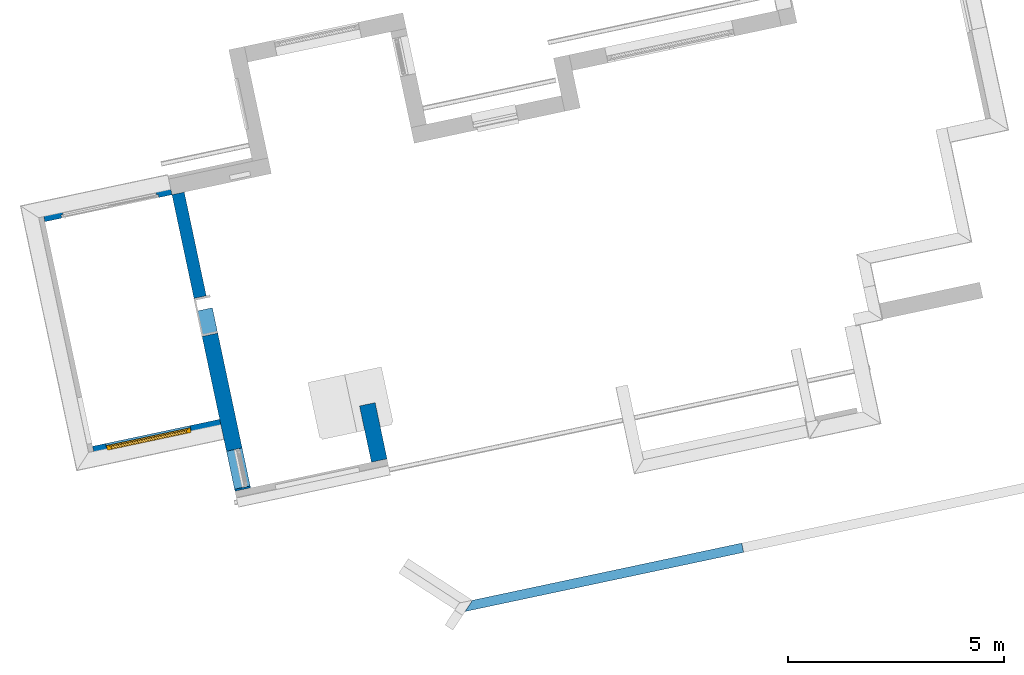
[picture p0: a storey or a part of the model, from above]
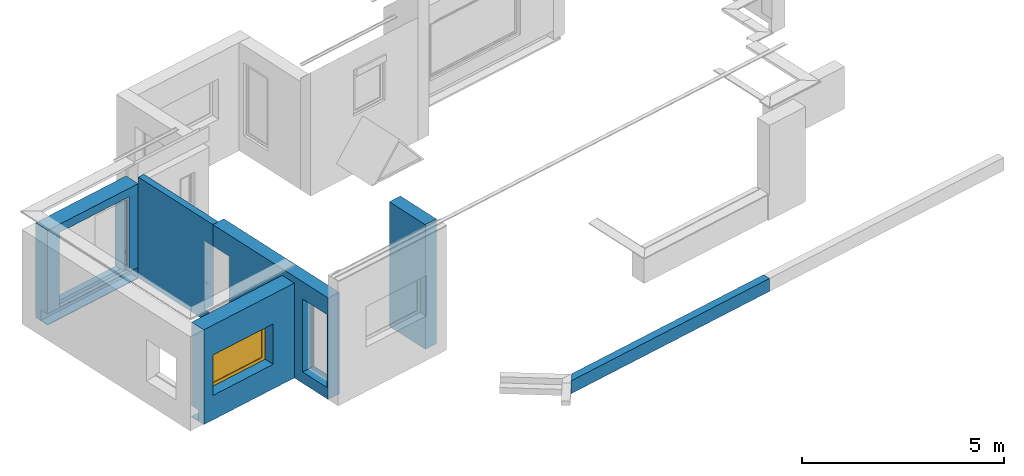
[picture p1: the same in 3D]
Properties of the parts of a building model (IFC2X3)

# File
Description: ViewDefinition [CoordinationView_V2.0], RevitIdentifiers [VersionGUID: 4ad54dfb-f86c-4c14-92f9-87bb07114b9b, NumberOfSaves: 84], CoordinateReference [CoordinateBase: Coordonnées partagées actuelles]
File name: MAI-1014-PORDIC
Time: 2024-04-09T16:30:19
Written by: The EXPRESS Data Manager Version 5.02.0100.07 : 28 Aug 2013
Made in: 22.0.2.392 - Exporter 22.6.0.0 - Interface alternative d'export 22.6.0.0
Comment: STEP Physical File produced by: The EXPRESS Data Manager Version 5.02.0100.07 : 28 Aug 2013 * Module: EDMstepFileFactory/EDMstandAlone * Creation date: Tue Apr 09 16:30:19 2024 * Host: LAPTOP-C1R9780E * Database: C:\Users\olivier\AppData\Local\Temp\71b0d7dc-91db-41fd-8e0b-7346815324da\59c9abdc-0e41-45ae-9ef3-d0277ee2119c\ifc * Database version: 5507 * Database creation date: Tue Apr 09 16:30:01 2024 * Schema: IFC2X3 * Model: DataRepository.ifc * Model creation date: Tue Apr 09 16:30:05 2024 * Header model: DataRepository.ifc_HeaderModel * Header model creation date: Tue Apr 09 16:30:05 2024 * EDMuser: sdai-user * EDMgroup: sdai-group * License ID and type: 5605 : Permanent license. Expiry date: * EDMstepFileFactory options: 020000

# IfcProject, MAI-1014-PORDIC
LongName: Extension d'une maison individuelle à Pordic; Phase: PC

# IfcSite, Surface:739914
RefLatitude: 48, 35, 2, 357482; RefLongitude: -2, -47, -1, -321678; RefElevation: 0 cm

# IfcBuilding
Pset_BuildingCommon - NumberOfStoreys: 7

# IfcBuildingStorey: Niveau:Ligne du (SD) Niveau_Projet 200, ***R+1 (SD)***
LongName: ***R+1 (SD)***; Elevation: 269 cm

# IfcBuildingStorey: Niveau:Ligne du Niveau (SD)_Partagée NGF 200 (2)
Name | LongName | Elevation (cm)
Rez de chaussée (SD) | Rez de chaussée (SD) | -17
***R+2 (SD)*** | ***R+2 (SD)*** | 522

# IfcBuildingStorey: Niveau:Ligne du Niveau_Partagée NGF 200, _R+2
LongName: _R+2; Elevation: 544 cm

# IfcBuildingStorey: Niveau:Ligne du Niveau_Projet 200 (3)
Name | LongName | Elevation (cm)
_Rez de chaussée Séjour | _Rez de chaussée Séjour | 2.07728e-10
Rez de chaussée | Rez de chaussée | 17
_R+1 | _R+1 | 289

# IfcSpace: Bain Etage 9:4713626, 9
In: _R+1
LongName: Bain Etage; InteriorOrExteriorSpace: INTERNAL
Pset_SpaceCommon - Reference: Bain Etage 9

# IfcSpace: Bain2 Etage 14:4713631, 14
In: _R+1
LongName: Bain2 Etage; InteriorOrExteriorSpace: INTERNAL
Pset_SpaceCommon - Reference: Bain2 Etage 14

# IfcSpace: Buanderie 10:4713627, 10
In: _R+1
LongName: Buanderie; InteriorOrExteriorSpace: INTERNAL
Pset_SpaceCommon - Reference: Buanderie 10

# IfcSpace: Buanderie ccc:4481670, ccc
In: _Rez de chaussée Séjour
LongName: Buanderie; InteriorOrExteriorSpace: INTERNAL
Pset_SpaceCommon - Reference: Buanderie ccc

# IfcSpace: Chambre 1 lll:4844613, lll
In: _Rez de chaussée Séjour
LongName: Chambre 1; InteriorOrExteriorSpace: INTERNAL
Pset_SpaceCommon - Reference: Chambre 1 lll

# IfcSpace: Chambre 11:4713628, 11
In: _R+1
LongName: Chambre; InteriorOrExteriorSpace: INTERNAL
Pset_SpaceCommon - Reference: Chambre 11

# IfcSpace: Chambre 15:4713632, 15
In: _R+1
LongName: Chambre; InteriorOrExteriorSpace: INTERNAL
Pset_SpaceCommon - Reference: Chambre 15

# IfcSpace: Chambre 2 zz:4481613, zz
In: _Rez de chaussée Séjour
LongName: Chambre 2; InteriorOrExteriorSpace: INTERNAL
Pset_SpaceCommon - Reference: Chambre 2 zz

# IfcSpace: Chambre 3 aaa:4481619, aaa
In: _Rez de chaussée Séjour
LongName: Chambre 3; InteriorOrExteriorSpace: INTERNAL
Pset_SpaceCommon - Reference: Chambre 3 aaa

# IfcSpace: Cuisine jjj:4483339, jjj
In: _Rez de chaussée Séjour
LongName: Cuisine; InteriorOrExteriorSpace: INTERNAL
Pset_SpaceCommon - Reference: Cuisine jjj

# IfcSpace: Dgt. 13:4713630, 13
In: _R+1
LongName: Dgt.; InteriorOrExteriorSpace: INTERNAL
Pset_SpaceCommon - Reference: Dgt. 13

# IfcSpace: Dgt. 16:4717892, 16
In: _R+1
LongName: Dgt.; InteriorOrExteriorSpace: INTERNAL
Pset_SpaceCommon - Reference: Dgt. 16

# IfcSpace: Dgt. ddd:4481676, ddd
In: _Rez de chaussée Séjour
LongName: Dgt.; InteriorOrExteriorSpace: INTERNAL
Pset_SpaceCommon - Reference: Dgt. ddd

# IfcSpace: Espace vert 12:2006179, 12
In: _Rez de chaussée Séjour
LongName: Espace vert; InteriorOrExteriorSpace: INTERNAL; Group: PARCELLES
Pset_SpaceCommon - Reference: Espace vert 12

# IfcSpace: Hall fff:4481931, fff
In: _Rez de chaussée Séjour
LongName: Hall; InteriorOrExteriorSpace: INTERNAL
Pset_SpaceCommon - Reference: Hall fff

# IfcSpace: Lot 1 8:2006171, 8
In: _Rez de chaussée Séjour
LongName: Lot 1; InteriorOrExteriorSpace: INTERNAL; Group: PARCELLES
Pset_SpaceCommon - Reference: Lot 1 8

# IfcSpace: Lot 2 10:2006175, 10
In: _Rez de chaussée Séjour
LongName: Lot 2; InteriorOrExteriorSpace: INTERNAL; Group: PARCELLES
Pset_SpaceCommon - Reference: Lot 2 10

# IfcSpace: Lot 3 11:2006177, 11
In: _Rez de chaussée Séjour
LongName: Lot 3; InteriorOrExteriorSpace: INTERNAL; Group: PARCELLES
Pset_SpaceCommon - Reference: Lot 3 11

# IfcSpace: Mezzanine 12:4713629, 12
In: _R+1
LongName: Mezzanine; InteriorOrExteriorSpace: INTERNAL
Pset_SpaceCommon - Reference: Mezzanine 12

# IfcSpace: SDE eee:4481930, eee
In: _Rez de chaussée Séjour
LongName: SDE; InteriorOrExteriorSpace: INTERNAL
Pset_SpaceCommon - Reference: SDE eee

# IfcSpace: SDE yy:4481608, yy
In: _Rez de chaussée Séjour
LongName: SDE; InteriorOrExteriorSpace: INTERNAL
Pset_SpaceCommon - Reference: SDE yy

# IfcSpace: STnd 159:1942835, 159
In: _Rez de chaussée Séjour
LongName: STnd; InteriorOrExteriorSpace: INTERNAL; Group: SURFACE DE PLANCHER (existant)
Pset_SpaceCommon - Reference: STnd 159

# IfcSpace: STnd 1:4682735, 1
In: _Rez de chaussée Séjour
LongName: STnd; InteriorOrExteriorSpace: INTERNAL; Group: SURFACE DE PLANCHER (projet)
Pset_SpaceCommon - Reference: STnd 1

# IfcSpace: Salle à manger iii:4483313, iii
In: _Rez de chaussée Séjour
LongName: Salle à manger; InteriorOrExteriorSpace: INTERNAL
Pset_SpaceCommon - Reference: Salle à manger iii

# IfcSpace: Surface affectée au stationnement des véhicules 216:1942263, 216
In: _Rez de chaussée Séjour
LongName: Surface affectée au stationnement des véhicules; InteriorOrExteriorSpace: INTERNAL; Group: Construction brute
Pset_SpaceCommon - Reference: Surface affectée au stationnement des véhicules 216

# IfcSpace: Surface affectée à l'habitation 214:1942178, 214
In: _Rez de chaussée Séjour
LongName: Surface affectée à l'habitation; InteriorOrExteriorSpace: INTERNAL; Group: Construction brute
Pset_SpaceCommon - Reference: Surface affectée à l'habitation 214

# IfcSpace: Surface technique (RDC ou étage) 215:1942179, 215
In: _Rez de chaussée Séjour
LongName: Surface technique (RDC ou étage); InteriorOrExteriorSpace: INTERNAL; Group: Construction brute
Pset_SpaceCommon - Reference: Surface technique (RDC ou étage) 215

# IfcSpace: Surface technique (sous-sol ou combles) 218:1942282, 218
In: _Rez de chaussée Séjour
LongName: Surface technique (sous-sol ou combles); InteriorOrExteriorSpace: INTERNAL; Group: Construction brute
Pset_SpaceCommon - Reference: Surface technique (sous-sol ou combles) 218

# IfcSpace: Surfaces non closes en RDC, balcons et toitures terrasses 217:1942277, 217
In: _Rez de chaussée Séjour
LongName: Surfaces non closes en RDC, balcons et toitures terrasses; InteriorOrExteriorSpace: INTERNAL; Group: Construction brute
Pset_SpaceCommon - Reference: Surfaces non closes en RDC, balcons et toitures terrasses 217

# IfcSpace: Séjour / Jardin ggg:4482516, ggg
In: _Rez de chaussée Séjour
LongName: Séjour / Jardin; InteriorOrExteriorSpace: INTERNAL
Pset_SpaceCommon - Reference: Séjour / Jardin ggg

# IfcSpace: Séjour / Mer hhh:4482627, hhh
In: _Rez de chaussée Séjour
LongName: Séjour / Mer; InteriorOrExteriorSpace: INTERNAL
Pset_SpaceCommon - Reference: Séjour / Mer hhh

# IfcSpace: Voirie 9:2006173, 9
In: _Rez de chaussée Séjour
LongName: Voirie; InteriorOrExteriorSpace: INTERNAL; Group: PARCELLES
Pset_SpaceCommon - Reference: Voirie 9

# IfcSpace: Wc mmm:4934494, mmm
In: _Rez de chaussée Séjour
LongName: Wc; InteriorOrExteriorSpace: INTERNAL
Pset_SpaceCommon - Reference: Wc mmm

# IfcBeam: Poutre - Bois de construction de dimensions courantes:100x280, Poutre - Bois de construction de dimensions courantes:100x280:5055540
In: ***R+1 (SD)***
Type - Pset_BeamCommon - LoadBearing: yes; IsExternal: no
Material: Bois - Bois de construction de dimensions courantes
Pset_BeamCommon - Reference: 100x280; Span: 189 cm; Slope: 0 deg
Pset_QuantityTakeOff - Reference: 100x280; sets with these values: 2

# IfcBuildingElementProxy: 5028824
In: Rez de chaussée (SD)
Pset_ProvisionForVoid - Shape: Undefined

# IfcBuildingElementProxy: 5114860
In: Rez de chaussée (SD)
Pset_ProvisionForVoid - Shape: Undefined

# IfcBuildingElementProxy: Bord de toiture:Profil Ardoise, Bord de toiture:Profil Ardoise:5044503
In: ***R+2 (SD)***
Pset_BuildingElementProxyCommon - Reference: Profil Ardoise; sets with these values: 2

# IfcBuildingElementProxy: Lave-Mains 40x24:40x24, Lave-Mains 40x24:40x24:4976055
In: mmm
Type - Material: <Unnamed>
Pset_BuildingElementProxyCommon - Reference: 40x24; sets with these values: 2

# IfcBuildingElementProxy: PLANTE- Conifères divers:Pin en tige remontée_ Grand (3)
In: _Rez de chaussée Séjour
Type - Material: <Unnamed>
Classification: G2050500 Uniformat (Uniformat)
Pset_BuildingElementProxyCommon - Reference: Pin en tige remontée_ Grand; sets with these values: 2
Name (PLANTE- Conifères divers:Pin en tige remontée_ Grand:...)
4941498
4942555
5015873

# IfcBuildingElementProxy: PLANTE- Conifères divers:Pin en tige remontée_ Petit (3)
In: _Rez de chaussée Séjour
Type - Material: <Unnamed>
Classification: G2050500 Uniformat (Uniformat)
Pset_BuildingElementProxyCommon - Reference: Pin en tige remontée_ Petit; sets with these values: 2
Name (PLANTE- Conifères divers:Pin en tige remontée_ Petit:...)
4942507
5015922
5015967

# IfcBuildingElementProxy: RES- REGARD:Regard EP 60*60, RES- REGARD:Regard EP 60*60:5132817
In: Rez de chaussée
Type - Material: <Unnamed>
Pset_BuildingElementProxyCommon - Reference: Regard EP 60*60; sets with these values: 2
Pset_ProvisionForVoid - Width: 60 cm; Height: 60 cm; Depth: 60 cm

# IfcBuildingElementProxy: RES_EP - BARBACANE:5x20 (3)
In: _R+1
Type - Material: <Unnamed>
Pset_BuildingElementProxyCommon - Reference: 5x20; sets with these values: 2
Name (RES_EP - BARBACANE:5x20:...)
5134526
5134740
5135031

# IfcBuildingElementProxy: RES_EP - BOITE A EAU:Descente EP _Alu gris clair (3)
In: _R+1
Type - Material: __ ALU_ton gris (descentes EP)
Pset_BuildingElementProxyCommon - Reference: Descente EP _Alu gris clair; sets with these values: 2
Pset_ProvisionForVoid - Width: 20 cm; Height: 20 cm; Depth: 20 cm
Name (RES_EP - BOITE A EAU:Descente EP _Alu gris clair:...)
5130607
5131939
5138986

# IfcColumn: Poteau alu - Carré:20x20, Poteau alu - Carré:20x20:5078782
In: _Rez de chaussée Séjour
Type - PredefinedType: COLUMN; Material: __ METAL_gris foncé (menuiseries acier)______________________TEST
Type - Pset_ColumnCommon - LoadBearing: yes; IsExternal: no
Pset_ColumnCommon - Reference: 20x20
Pset_QuantityTakeOff - Reference: 20x20; sets with these values: 2

# IfcCovering: Plafond composé:*BA13+ suspentes métalliques ISO 30 (4)
In: ***R+1 (SD)***
Type - PredefinedType: CEILING
Type - Pset_CoveringCommon - TotalThickness: 32 cm
Material: Laine minérale 30 cm, __ BA 13 2 cm
Pset_CoveringCommon - Reference: *BA13+ suspentes métalliques ISO 30; sets with these values: 2
Name (Plafond composé:*BA13+ suspentes métalliques ISO 30:...)
4829692
5046348
5074606
5139370

# IfcCurtainWall: Mur-rideau:*Mur-rideau (5)
Type - Pset_CurtainWallCommon - IsExternal: yes
Pset_CurtainWallCommon - Reference: *Mur-rideau
Pset_QuantityTakeOff - Reference: *Mur-rideau
Name (Mur-rideau:*Mur-rideau:...) | In
4793220 | _Rez de chaussée Séjour
4793331 | _R+1
4838392 | _Rez de chaussée Séjour
4839396 | _Rez de chaussée Séjour
5005422 | _Rez de chaussée Séjour

# IfcDoor: *Coulissante - Encastrée:PC 230 x 204 (galandage), *Coulissante - Encastrée:PC 230 x 204 (galandage):4812745
In: _Rez de chaussée Séjour
Type - OperationType: SLIDING_TO_LEFT; ParameterTakesPrecedence: no; Sizeable: no; Material: <Unnamed>
Type - *Coulissante - Encastrée:PC 230 x 204 (galandage):4812745:1 - PanelOperation: SLIDING
Type - Pset_DoorCommon - IsExternal: no
OverallHeight: 206.5 cm; OverallWidth: 460 cm
Pset_DoorCommon - Reference: PC 230 x 204 (galandage)
Pset_QuantityTakeOff - Reference: PC 230 x 204 (galandage)

# IfcDoor: *Coulissante - Encastrée:PC 80 x 204 (galandage), *Coulissante - Encastrée:PC 80 x 204 (galandage):4673256
In: Rez de chaussée
Type - OperationType: SLIDING_TO_LEFT; ParameterTakesPrecedence: no; Sizeable: no; Material: <Unnamed>
Type - *Coulissante - Encastrée:PC 80 x 204 (galandage):4673256:1 - PanelOperation: SLIDING
Type - Pset_DoorCommon - IsExternal: no
OverallHeight: 206.5 cm; OverallWidth: 164 cm
Pset_DoorCommon - Reference: PC 80 x 204 (galandage)
Pset_QuantityTakeOff - Reference: PC 80 x 204 (galandage)

# IfcDoor: *Porte_alveolaire:Pa 73 x 204, *Porte_alveolaire:Pa 73 x 204:4861944
In: _R+1
Type - ParameterTakesPrecedence: no; Sizeable: no; Material: <Unnamed>
Type - Pset_DoorCommon - IsExternal: no
OverallHeight: 207.5 cm; OverallWidth: 80 cm
Pset_DoorCommon - Reference: Pa 73 x 204
Pset_QuantityTakeOff - Reference: Pa 73 x 204

# IfcDoor: *Porte_alveolaire:Pp 83 x 204 (13)
Type - ParameterTakesPrecedence: no; Sizeable: no; Material: <Unnamed>
Type - Pset_DoorCommon - IsExternal: no
OverallHeight: 207.5 cm; OverallWidth: 90 cm
Pset_DoorCommon - Reference: Pp 83 x 204
Pset_QuantityTakeOff - Reference: Pp 83 x 204
Name (*Porte_alveolaire:Pp 83 x 204:...) | In
4639951 | Rez de chaussée
4685772 | _R+1
4686029 | _R+1
4686187 | _R+1
4687985 | _R+1
4688013 | _R+1
4827529 | Rez de chaussée
4827531 | Rez de chaussée
4870077 | _Rez de chaussée Séjour
4919026 | Rez de chaussée
5102498 | Rez de chaussée
5102815 | Rez de chaussée
5138515 | _Rez de chaussée Séjour

# IfcDoor: Ouverture en rectangle:Ouverture en rectangle, Ouverture en rectangle:Ouverture en rectangle:5138474
In: _Rez de chaussée Séjour
Type - ParameterTakesPrecedence: no; Sizeable: no; Material: Bois - Chêne
Type - Pset_DoorCommon - IsExternal: no
OverallHeight: 210 cm; OverallWidth: 82 cm
Pset_DoorCommon - Reference: Ouverture en rectangle
Pset_QuantityTakeOff - Reference: Ouverture en rectangle

# IfcDoor: PVC Panneau Vitré - Traverse:P oculus 93x210, PVC Panneau Vitré - Traverse:P oculus 93x210:4785177
In: Rez de chaussée
Type - OperationType: SINGLE_SWING_RIGHT; ParameterTakesPrecedence: no; Sizeable: no; Material: PVC - Blanc, Verre
Type - PVC Panneau Vitré - Traverse:P oculus 93x210:4785177:1 - PanelOperation: SWINGING
Type - Pset_DoorCommon - IsExternal: no; ThermalTransmittance: 5.5617 kg/K/s3
OverallHeight: 215 cm; OverallWidth: 103 cm
Pset_DoorCommon - Reference: P oculus 93x210
Pset_QuantityTakeOff - Reference: P oculus 93x210

# IfcDoor: PVC Panneau Vitré - Traverse:Pv 83x204, PVC Panneau Vitré - Traverse:Pv 83x204:4874728
In: _Rez de chaussée Séjour
Type - OperationType: SINGLE_SWING_RIGHT; ParameterTakesPrecedence: no; Sizeable: no; Material: PVC - Blanc, Verre
Type - PVC Panneau Vitré - Traverse:Pv 83x204:4874728:1 - PanelOperation: SWINGING
Type - Pset_DoorCommon - IsExternal: no; ThermalTransmittance: 5.5617 kg/K/s3
OverallHeight: 209 cm; OverallWidth: 93 cm
Pset_DoorCommon - Reference: Pv 83x204
Pset_QuantityTakeOff - Reference: Pv 83x204

# IfcFlowSegment: Gouttière:Gouttière_ronde:5003742 (2)
In: Rez de chaussée (SD)
Type - ElementType: Gouttière:Gouttière_ronde:5003742; PredefinedType: GUTTER
Pset_DistributionFlowElementCommon - Reference: Gouttière_ronde; sets with these values: 2
Pset_FlowSegmentDuctSegment - sets with these values: 2
Pset_PipeSegmentTypeGutter - Slope: 40.0594 deg
Name (Gouttière:Gouttière_ronde:...) | Length (cm)
5044310 | 208.158
5108160 | 1504.14

# IfcFlowTerminal: *AS - LAVABO sur pied:Lavabo sur pied, *AS - LAVABO sur pied:Lavabo sur pied:4979351
In: yy
Type - Material: <Unnamed>
Pset_DistributionFlowElementCommon - Reference: Lavabo sur pied; sets with these values: 2

# IfcFlowTerminal: AS- ELEMENT CUISINE:60 x p65cm_ LV, AS- ELEMENT CUISINE:60 x p65cm_ LV:4876975
In: jjj
Type - Material: MOBILIER- Cuisine
Pset_DistributionFlowElementCommon - Reference: 60 x p65cm_ LV; sets with these values: 2

# IfcFlowTerminal: AS- ELEMENT CUISINE:60 x p65cm_R, AS- ELEMENT CUISINE:60 x p65cm_R:4877630
In: jjj
Type - Material: MOBILIER- Cuisine
Pset_DistributionFlowElementCommon - Reference: 60 x p65cm_R; sets with these values: 2

# IfcFlowTerminal: Cuvette réservoir:Cuvette réservoir, Cuvette réservoir:Cuvette réservoir:5105952
In: yy
Type - Material: Porcelaine - Lin, Stratifié - Lin, Mat
Pset_DistributionFlowElementCommon - Reference: Cuvette réservoir; sets with these values: 2

# IfcFurnishingElement: Serena 4023:160x190, Serena 4023:160x190:5089534
In: lll
Type - Material: Plastic, Gypsum Board, Birch_horr
Type - Pset_ManufacturerTypeInformation - Manufacturer: Stolab
Pset_QuantityTakeOff - Reference: 160x190

# IfcMember: Meneau rectangulaire:Métal 5x5 cm_bord bas (2)
In: _R+1
Type - PredefinedType: MULLION; Material: __ METAL_gris foncé (menuiseries acier)______________________TEST
Type - Pset_MemberCommon - IsExternal: no
Pset_MemberCommon - IsExternal: yes; Reference: Métal 5x5 cm_bord bas
Pset_QuantityTakeOff - Reference: Métal 5x5 cm_bord bas
Name (Meneau rectangulaire:Métal 5x5 cm_bord bas:...) | Span (cm)
4795885 | 35.9852
4992266 | 169.419

# IfcMember: Meneau rectangulaire:Métal 5x5 cm_bord haut (18)
In: _R+1
Type - PredefinedType: MULLION; Material: __ METAL_gris foncé (menuiseries acier)______________________TEST
Type - Pset_MemberCommon - IsExternal: no
Pset_MemberCommon - Reference: Métal 5x5 cm_bord haut
Pset_QuantityTakeOff - Reference: Métal 5x5 cm_bord haut
Name (Meneau rectangulaire:Métal 5x5 cm_bord haut:...) | Span (cm)
4795853 | 172.322 | Pset_MemberCommon - IsExternal: yes
4795857 | 172.322 | Pset_MemberCommon - IsExternal: yes
4795859 | 172.322 | Pset_MemberCommon - IsExternal: yes
4992204 | 177.322 | Pset_MemberCommon - IsExternal: yes
5004717 | 100 | Pset_MemberCommon - IsExternal: yes
5004718 | 100 | Pset_MemberCommon - IsExternal: yes
5004719 | 110.5 | Pset_MemberCommon - IsExternal: yes
5004720 | 69.6419 | Pset_MemberCommon - IsExternal: yes
5012550 | 177.322 | Pset_MemberCommon - IsExternal: yes
4801789 | 119.578
4801794 | 101
4840248 | 109.578
4840255 | 119.578
4840259 | 94
4840260 | 9.5
5035786 | 9.5
5035787 | 94
5035788 | 101

# IfcMember: Meneau rectangulaire:Métal 5x5 cm_centré_milieu (26)
In: _Rez de chaussée Séjour
Type - PredefinedType: MULLION; Material: __ METAL_gris foncé (menuiseries acier)______________________TEST
Type - Pset_MemberCommon - IsExternal: no
Pset_MemberCommon - Reference: Métal 5x5 cm_centré_milieu
Pset_QuantityTakeOff - Reference: Métal 5x5 cm_centré_milieu
Name (Meneau rectangulaire:Métal 5x5 cm_centré_milieu:...) | Span (cm)
4795830 | 295.141 | Pset_MemberCommon - IsExternal: yes
4795836 | 295.141 | Pset_MemberCommon - IsExternal: yes
4795839 | 295.141 | Pset_MemberCommon - IsExternal: yes
4795842 | 295.141 | Pset_MemberCommon - IsExternal: yes
4795846 | 295.141 | Pset_MemberCommon - IsExternal: yes
4991913 | 67.1419 | Pset_MemberCommon - IsExternal: yes
4991914 | 95 | Pset_MemberCommon - IsExternal: yes
4991915 | 95 | Pset_MemberCommon - IsExternal: yes
4991916 | 107.5 | Pset_MemberCommon - IsExternal: yes
4838394 | 189.509
4838395 | 98.5
4838398 | 101
4838401 | 189.509
4838402 | 189.509
4839399 | 50
4839402 | 57.3931
4839405 | 152.5
4886312 | 160
5035782 | 45.9571
5036088 | 11.3772
5036089 | 22.4307
5036114 | 54.8931
5036149 | 57.3931
5036150 | 50
5005424 | 304.969
5005425 | 166.5

# IfcOpeningElement: Opening (61)
Name | In
Mur de base:*BRIQUE 37 (20 +INT 13+2 + EXT 2) (Iso+BA13)(enduit):4329863:1 | Rez de chaussée (SD) | Pset_OpeningElementCommon - Reference: *BRIQUE 37 (20 +INT 13+2 + EXT 2) (Iso+BA13)(enduit); sets with these values: 2
Mur de base:*BRIQUE 37 (20 +INT 13+2 + EXT 2) (Iso+BA13)(enduit):4329863:2 | Rez de chaussée (SD) | Pset_OpeningElementCommon - Reference: *BRIQUE 37 (20 +INT 13+2 + EXT 2) (Iso+BA13)(enduit); sets with these values: 2
Mur de base:*BRIQUE 37 (20 +INT 13+2 + EXT 2) (Iso+BA13)(enduit):4329863 | Rez de chaussée (SD) | Pset_OpeningElementCommon - Reference: c 220x220 +VR; sets with these values: 2
Ouverture en rectangle:Ouverture en rectangle:5138474:1 | _Rez de chaussée Séjour
Mur de base:*BRIQUE 24 (20 + INT 2 + EXT 2) (enduit 2 faces):4329864 | Rez de chaussée | Pset_OpeningElementCommon - Reference: Pp 83 x 204; sets with these values: 2
Mur de base:*Cloison 72/48 cm:4478370 | Rez de chaussée | Pset_OpeningElementCommon - Reference: Pp 83 x 204; sets with these values: 2
Mur de base:*BRIQUE 37 (20 +INT 13+2 + EXT 2) (Iso+BA13)(parement):4482134 | Rez de chaussée (SD) | Pset_OpeningElementCommon - Reference: Mur vide angle séjour; sets with these values: 2
Mur de base:*BRIQUE 37 (20 +INT 13+2 + EXT 2) (Iso+BA13)(parement):4482134 | Rez de chaussée (SD) | Pset_OpeningElementCommon - Reference: c 300x220; sets with these values: 2
Mur de base:*BRIQUE 37 (20 +INT 13+2 + EXT 2) (Iso+BA13)(parement):4482134 | Rez de chaussée (SD) | Pset_OpeningElementCommon - Reference: PC 230 x 204 (galandage); sets with these values: 2
Mur de base:*Mur (45) maçonné isolé + parement pierre:4484906:1 | Rez de chaussée (SD) | Pset_OpeningElementCommon - Reference: *Mur (45) maçonné isolé + parement pierre; sets with these values: 2
Mur de base:*Mur (45) maçonné isolé + parement pierre:4756898 | Rez de chaussée (SD) | Pset_OpeningElementCommon - Reference: *Mur-rideau; sets with these values: 2
*Porte_alveolaire:Pp 83 x 204:5102815:1 | Rez de chaussée
*Porte_alveolaire:Pp 83 x 204:5102498:1 | Rez de chaussée (SD)
Mur de base:*BRIQUE 37 (20 +INT 13+2 + EXT 2) (Iso+BA13)(enduit):5020648 | Rez de chaussée (SD)
Mur de base:*BETON 22 (20 + EXT 2) (parement) + couronnement zinc:4796458 | ***R+1 (SD)*** | Pset_OpeningElementCommon - Reference: 120x120; sets with these values: 2
Mur de base:*BETON 20:4812454 | _Rez de chaussée Séjour | Pset_OpeningElementCommon - Reference: fixe 110x220; sets with these values: 2
Mur de base:*BETON 20:4812454 | _Rez de chaussée Séjour | Pset_OpeningElementCommon - Reference: Mur vide angle séjour; sets with these values: 2
Mur de base:*BETON 20:4812454 | _Rez de chaussée Séjour | Pset_OpeningElementCommon - Reference: c 300x220; sets with these values: 2
Mur de base:*Mur (45) maçonné isolé + parement pierre:4832463:1 | Rez de chaussée (SD) | Pset_OpeningElementCommon - Reference: *Mur (45) maçonné isolé + parement pierre; sets with these values: 2
Mur de base:*Mur (45) maçonné isolé + parement pierre:4834276:1 | Rez de chaussée (SD) | Pset_OpeningElementCommon - Reference: *Mur (45) maçonné isolé + parement pierre; sets with these values: 2
Mur de base:*Mur (45) maçonné isolé + parement pierre:4834276 | Rez de chaussée (SD) | Pset_OpeningElementCommon - Reference: PF 80*220+VR; sets with these values: 2
Mur de base:*Mur (45) maçonné isolé + parement pierre:4969493 | Rez de chaussée (SD) | Pset_OpeningElementCommon - Reference: fixe 110x220; sets with these values: 2
Mur de base:*BRIQUE 37 (20 +INT 13+2 + EXT 2) (Iso+BA13)(enduit):5020648 | Rez de chaussée (SD) | Pset_OpeningElementCommon - Reference: Pp 83 x 204; sets with these values: 2
2 x Mur de base:*BRIQUE 37 (20 +INT 6+2 + EXT 2) (Iso+BA13)(enduit):5071584 | Rez de chaussée (SD) | Pset_OpeningElementCommon - Reference: Pp 83 x 204; sets with these values: 2
Mur de base:*BRIQUE 37 (20 +INT 6+2 + EXT 2) (Iso+BA13)(enduit):5071584 | Rez de chaussée (SD) | Pset_OpeningElementCommon - Reference: PF 90*220; sets with these values: 2
Mur de base:*Mur (45) maçonné isolé + parement pierre:4969493 | Rez de chaussée (SD)
Mur de base:*Mur (8) Parement pierre:5080823 | Rez de chaussée (SD) | Pset_OpeningElementCommon - Reference: OPTIMAL Top Turn Single Window 50x100; sets with these values: 2
Mur de base:*Mur (8) Parement pierre:5080823 | Rez de chaussée (SD) | Pset_OpeningElementCommon - Reference: c 220x220 +VR; sets with these values: 2
Mur de base:*BRIQUE 37 (20 +INT 13+2 + EXT 2) (Iso+BA13)(enduit):4329848 | Rez de chaussée (SD)
Mur de base:*BRIQUE 37 (20 +INT 13+2 + EXT 2) (Iso+BA13)(enduit):4329857 | Rez de chaussée
OPTIMAL Top Turn Single Window-1:OPTIMAL Top Turn Single Window 50x100:4329901:1 | Rez de chaussée (SD)
OPTIMAL Top Turn Single Window-1:200x120 PVC:4329899:1 | Rez de chaussée (SD)
Mur de base:*BRIQUE 37 (20 +INT 13+2 + EXT 2) (Iso+BA13)(enduit):4329866 | Rez de chaussée (SD)
Mur de base:*BRIQUE 37 (20 +INT 13+2 + EXT 2) (Iso+BA13)(enduit):4329877 | Rez de chaussée (SD)
OPTIMAL Top Turn Single Window-1:200x120 PVC:4329908:1 | _R+1
*Porte_alveolaire:Pp 83 x 204:4687985:1 | _R+1
Mur de base:*BRIQUE 37 (20 +INT 13+2 + EXT 2) (Iso+BA13)(enduit):4329906 | _R+1
*Porte_alveolaire:Pp 83 x 204:4827531:1 | Rez de chaussée
OPTIMAL Top Turn Single Window-1:fixe 110x220:4931289:1 | Rez de chaussée (SD)
*Porte_alveolaire:Pp 83 x 204:5138515:1 | _Rez de chaussée Séjour
Mur de base:*Mur (45) maçonné isolé + parement pierre:4483016 | _Rez de chaussée Séjour
Mur de base:*Mur (45) maçonné isolé + parement pierre:4484906 | Rez de chaussée (SD)
OPTIMAL Top Turn Single Window-1:c 300x170 +VR:4487097:1 | Rez de chaussée (SD)
*Porte_alveolaire:Pp 83 x 204:4639951:1 | Rez de chaussée
Mur de base:*Cloison 72/48 cm:5122360 | Rez de chaussée
*Porte_alveolaire:Pp 83 x 204:4685772:1 | _R+1
*Porte_alveolaire:Pp 83 x 204:4686029:1 | _R+1
*Porte_alveolaire:Pp 83 x 204:4686187:1 | _R+1
*Porte_alveolaire:Pp 83 x 204:4688013:1 | _R+1
Mur de base:*BRIQUE 37 (20 +INT 13+2 + EXT 2) (Iso+BA13)(parement):4785176 | Rez de chaussée
Mur de base:*BETON 20:4812454 | _Rez de chaussée Séjour
*Porte_alveolaire:Pp 83 x 204:4870077:1 | _Rez de chaussée Séjour
*Porte_alveolaire:Pp 83 x 204:4827529:1 | Rez de chaussée
OPTIMAL Top Turn Single Window-1:200x120 +VR:4832554:1 | Rez de chaussée (SD)
OPTIMAL Top Turn Single Window-1:200x120 +VR:4833477:1 | Rez de chaussée (SD)
Mur de base:*Mur (45) maçonné isolé + parement pierre:4834276 | Rez de chaussée (SD)
Mur de base:*BRIQUE 37 (20 +INT 13+2 + EXT 2) (Iso+BA13)(parement):4834657 | _Rez de chaussée Séjour
*Porte_alveolaire:Pa 73 x 204:4861944:1 | ***R+1 (SD)***
Mur de base:*Cloison 72/48 cm:4872756 | _Rez de chaussée Séjour
*Porte_alveolaire:Pp 83 x 204:4919026:1 | _Rez de chaussée Séjour

# IfcPlate: Panneau système:*Vitré (centré) (9)
In: _Rez de chaussée Séjour
Type - PredefinedType: CURTAIN_PANEL; Material: Fenêtre - Vitrage
Type - Pset_PlateCommon - IsExternal: no
Pset_PlateCommon - Reference: *Vitré (centré)
Pset_QuantityTakeOff - Reference: *Vitré (centré)
Name (Panneau système:*Vitré (centré):...)
4793221 | Pset_PlateCommon - IsExternal: yes
4795680 | Pset_PlateCommon - IsExternal: yes
4795751 | Pset_PlateCommon - IsExternal: yes
4795792 | Pset_PlateCommon - IsExternal: yes
4838393
4838397
4839401
4885618
5005423

# IfcPlate: Panneau système:*Vitré (décalé) (8)
In: _R+1
Type - PredefinedType: CURTAIN_PANEL; Material: Fenêtre - Vitrage
Type - Pset_PlateCommon - IsExternal: no
Pset_PlateCommon - Reference: *Vitré (décalé)
Pset_QuantityTakeOff - Reference: *Vitré (décalé)
Name (Panneau système:*Vitré (décalé):...)
4792704 | Pset_PlateCommon - IsExternal: yes
4792707 | Pset_PlateCommon - IsExternal: yes
4792709 | Pset_PlateCommon - IsExternal: yes
4792711 | Pset_PlateCommon - IsExternal: yes
4793332
4797091
4797094
4797096

# IfcRoof: Toit de base:Ardoise 5 (2)
Material: __ TOIT_ardoises______________________TEST 5 cm
Pset_QuantityTakeOff - Reference: Ardoise 5
Pset_RoofCommon - IsExternal: yes; Reference: Ardoise 5
Name (Toit de base:Ardoise 5:...) | In | TotalArea (m2)
4329932 | _R+1 | 6.06732 | Pset_RoofCommon - ProjectedArea: 3.9 m2
4329990 | _R+2 | 2.65996

# IfcRoof: Toit de base:Bac zinc Ep 23mm (3)
In: _R+1
Pset_QuantityTakeOff - Reference: Bac zinc Ep 23mm
Pset_RoofCommon - IsExternal: yes; Reference: Bac zinc Ep 23mm
Name (Toit de base:Bac zinc Ep 23mm:...) | ProjectedArea (m2) | TotalArea (m2)
4996809 | 2.36348 | 2.36926
5074894 | 29.3803 | 29.452
5080639 | 18.5479 | 18.5932

# IfcRoof: Toit de base:Toit ardoise ep 37, Toit de base:Toit ardoise ep 37:4486264
In: _R+1
Material: __ TOIT_ardoises______________________TEST 4 cm, Bois d'oeuvre, C16 10 cm, Laine minérale 22 cm, Panneau de revêtement en gypse 1 cm
Pset_QuantityTakeOff - Reference: Toit ardoise ep 37
Pset_RoofCommon - IsExternal: yes; Reference: Toit ardoise ep 37; ProjectedArea: 125.081 m2; TotalArea: 176.171 m2

# IfcRoof: Toit de base:Toiture ardoise (ep30cm) (2)
Material: __ TOIT_ardoises______________________TEST 30 cm
Pset_QuantityTakeOff - Reference: Toiture ardoise (ep30cm)
Pset_RoofCommon - IsExternal: yes; Reference: Toiture ardoise (ep30cm)
Name (Toit de base:Toiture ardoise (ep30cm):...) | In | ProjectedArea (m2) | TotalArea (m2)
4329947 | _R+1 | 6.3671 | 11.3862
4329981 | _R+2 | 15.3612 | 35.0416

# IfcRoof: Vitres inclinées:Toit en verre 1m x 2m (2)
In: _R+1
Type - Pset_CurtainWallCommon - IsExternal: yes
Pset_QuantityTakeOff - Reference: Toit en verre 1m x 2m
Pset_RoofCommon - IsExternal: yes; Reference: Toit en verre 1m x 2m
Name (Vitres inclinées:Toit en verre 1m x 2m:...) | ProjectedArea (m2)
4792600 | 6.90707
4797076 | 2.52881

# IfcSlab: Sol:*BETON 20, Sol:*BETON 20:4706564
In: _R+1
Type - PredefinedType: FLOOR; Material: Béton, précoulé 20 cm
Type - Pset_ReinforcementBarPitchOfSlab - Description: Dalle auto-protégée
Type - Pset_SlabCommon - IsExternal: no; ThermalTransmittance: 5.23 kg/K/s3
Pset_QuantityTakeOff - Reference: *BETON 20; sets with these values: 2
Pset_SlabCommon - LoadBearing: no; PitchAngle: 0 deg; Reference: *BETON 20

# IfcSlab: Sol:*BETON 32 (20 + Revêtement sur chape) (4)
Type - PredefinedType: FLOOR; Material: Dalle, carrelage 15 x 15 2 cm, __ ISOLANT (sous dalle) 8 cm, <Unnamed> 2 cm, Béton, précoulé 20 cm
Type - Pset_ReinforcementBarPitchOfSlab - Description: S6
Type - Pset_SlabCommon - IsExternal: no; ThermalTransmittance: 4.75455 kg/K/s3
Pset_QuantityTakeOff - Reference: *BETON 32 (20 + Revêtement sur chape); sets with these values: 2
Pset_SlabCommon - LoadBearing: no; Reference: *BETON 32 (20 + Revêtement sur chape); PitchAngle: 0 deg
Name (Sol:*BETON 32 (20 + Revêtement sur chape):...) | In
4627783 | Rez de chaussée | Material: Dalle, carrelage 15 x 15, __ ISOLANT (sous dalle), <Unnamed>, Béton, précoulé
4822113 | _Rez de chaussée Séjour
4822113:2 | _Rez de chaussée Séjour
5080058 | Rez de chaussée

# IfcSlab: Sol:// Terrasse__ Lames bois 22, Sol:// Terrasse__ Lames bois 22:4805989
In: _Rez de chaussée Séjour
Type - PredefinedType: FLOOR; Material: __ BOIS TERRASSE 2 cm, __ BOIS (charpente) 20 cm
Type - Pset_ReinforcementBarPitchOfSlab - Description: S9b
Type - Pset_SlabCommon - IsExternal: no
Pset_QuantityTakeOff - Reference: // Terrasse__ Lames bois 22; sets with these values: 2
Pset_SlabCommon - LoadBearing: no; PitchAngle: 0 deg; Reference: // Terrasse__ Lames bois 22

# IfcSlab: Sol:Béton + Lames bois, Sol:Béton + Lames bois:4681516
In: _Rez de chaussée Séjour
Type - PredefinedType: FLOOR; Material: __ BOIS TERRASSE 5 cm, __ SITE_pavés béton 35 cm
Type - Pset_SlabCommon - IsExternal: no
Pset_QuantityTakeOff - Reference: Béton + Lames bois; sets with these values: 2
Pset_SlabCommon - LoadBearing: no; PitchAngle: 0 deg; Reference: Béton + Lames bois

# IfcSlab: Terre-plein:Terre-plein Béton - 300 mm (3)
Type - PredefinedType: FLOOR; Material: <Unnamed> 30 cm
Type - Pset_SlabCommon - IsExternal: no
Pset_QuantityTakeOff - Reference: Terre-plein Béton - 300 mm; sets with these values: 2
Pset_SlabCommon - PitchAngle: 0 deg; Reference: Terre-plein Béton - 300 mm
Name (Terre-plein:Terre-plein Béton - 300 mm:...) | In
5017795 | _Rez de chaussée Séjour
5081552 | Rez de chaussée
5098557 | Rez de chaussée

# IfcSlab: Toit de base:Bac zinc Ep 23mm (3)
In: _R+1
Type - PredefinedType: ROOF
Type - Pset_ReinforcementBarPitchOfSlab - Description: Terrasson zinc
Type - Pset_SlabCommon - IsExternal: yes; ThermalTransmittance: 0.545455 kg/K/s3
Material: 1212.FINITION FACADE - Bardage Zinc ton gris 1 cm, Bois d'oeuvre, C16 22 cm
Pset_QuantityTakeOff - Reference: Bac zinc Ep 23mm; sets with these values: 2
Pset_SlabCommon - Reference: Bac zinc Ep 23mm; PitchAngle: 4 deg
Name (Toit de base:Bac zinc Ep 23mm:...)
4996809
5074894
5080639

# IfcStair: Escalier:*Bois - Limons à la Française (2)
In: Rez de chaussée
Name (Escalier:*Bois - Limons à la Française:...)
4702395 | Material: <Unnamed>
4702395 | Pset_QuantityTakeOff - Reference: *Bois - Limons à la Française; Pset_StairCommon - IsExternal: no; Reference: *Bois - Limons à la Française; NumberOfRiser: 13; NumberOfTreads: 12; RiserHeight: 18.2143 cm; TreadLength: 26.5714 cm

# IfcStair: Escalier:*Béton (extérieur) (2)
In: Rez de chaussée (SD)
Name (Escalier:*Béton (extérieur):...)
4804324 | Material: <Unnamed>
4804324 | Pset_QuantityTakeOff - Reference: *Béton (extérieur); Pset_StairCommon - IsExternal: no; Reference: *Béton (extérieur); NumberOfRiser: 2; NumberOfTreads: 2; RiserHeight: 18.5 cm; TreadLength: 26 cm

# IfcWall: Mur de base:*BETON 22 (20 + EXT 2) (enduit) + couronnement zinc (2)
In: ***R+1 (SD)***
Type - PredefinedType: STANDARD; Material: __ ENDUIT_Blanc 2 cm, __ ENDUIT_Blanc 20 cm
Type - Pset_ReinforcementBarPitchOfWall - Description: Couverture à coulisseau
Type - Pset_WallCommon - IsExternal: yes
Pset_QuantityTakeOff - Reference: *BETON 22 (20 + EXT 2) (enduit) + couronnement zinc; sets with these values: 2
Pset_WallCommon - ExtendToStructure: no; LoadBearing: no; Reference: *BETON 22 (20 + EXT 2) (enduit) + couronnement zinc
Name (Mur de base:*BETON 22 (20 + EXT 2) (enduit) + couronnement zinc:...)
4796639
5118324

# IfcWall: Mur de base:*BETON 22 (20 + EXT 2) (parement), Mur de base:*BETON 22 (20 + EXT 2) (parement):4804832
In: Rez de chaussée (SD)
Type - PredefinedType: STANDARD; Material: __ PIERRE______________________TEST 2 cm, __ BETON______________________TEST 20 cm
Type - Pset_ReinforcementBarPitchOfWall - Description: M1c
Type - Pset_WallCommon - IsExternal: yes
Pset_QuantityTakeOff - Reference: *BETON 22 (20 + EXT 2) (parement); sets with these values: 2
Pset_WallCommon - ExtendToStructure: no; LoadBearing: no; Reference: *BETON 22 (20 + EXT 2) (parement)

# IfcWall: Mur de base:*BETON 22 (20 + EXT 2) (parement) + couronnement zinc (3)
In: ***R+1 (SD)***
Type - PredefinedType: STANDARD; Material: __ PIERRE______________________TEST 10 cm, Béton, précoulé 20 cm
Type - Pset_ReinforcementBarPitchOfWall - Description: Couverture à coulisseau
Type - Pset_WallCommon - IsExternal: yes; ThermalTransmittance: 5.23 kg/K/s3
Pset_QuantityTakeOff - Reference: *BETON 22 (20 + EXT 2) (parement) + couronnement zinc; sets with these values: 2
Pset_WallCommon - ExtendToStructure: no; LoadBearing: no; Reference: *BETON 22 (20 + EXT 2) (parement) + couronnement zinc
Name (Mur de base:*BETON 22 (20 + EXT 2) (parement) + couronnement zinc:...)
4789510
4789796
4837759

# IfcWall: Mur de base:*BRIQUE 24 (20 + INT 2 + EXT 2) (enduit 2 faces) (3)
Type - PredefinedType: STANDARD; Material: __ ENDUIT_Blanc 2 cm, Béton, précoulé 20 cm, __ ENDUIT_Blanc 2 cm
Type - Pset_ReinforcementBarPitchOfWall - Description: M2c
Type - Pset_WallCommon - IsExternal: yes; ThermalTransmittance: 5.23 kg/K/s3
Pset_QuantityTakeOff - Reference: *BRIQUE 24 (20 + INT 2 + EXT 2) (enduit 2 faces); sets with these values: 2
Pset_WallCommon - ExtendToStructure: no; Reference: *BRIQUE 24 (20 + INT 2 + EXT 2) (enduit 2 faces)
Name (Mur de base:*BRIQUE 24 (20 + INT 2 + EXT 2) (enduit 2 faces):...) | In | LoadBearing
4485659 | _Rez de chaussée Séjour | yes
4638996 | _Rez de chaussée Séjour | yes
4639800 | Rez de chaussée | no

# IfcWall: Mur de base:*BRIQUE 37 (20 +INT 13+2 + EXT 2) (Iso+BA13)(enduit) (5)
Type - PredefinedType: STANDARD; Material: __ ENDUIT_Blanc 2 cm, __ BETON_parpaings 20 cm, __ ISOLANT (pat 1) 13 cm, __ ENDUIT_Blanc 2 cm
Type - Pset_ReinforcementBarPitchOfWall - Description: Enduit ton blanc
Type - Pset_WallCommon - IsExternal: yes
Pset_QuantityTakeOff - Reference: *BRIQUE 37 (20 +INT 13+2 + EXT 2) (Iso+BA13)(enduit); sets with these values: 2
Pset_WallCommon - Reference: *BRIQUE 37 (20 +INT 13+2 + EXT 2) (Iso+BA13)(enduit)
Name (Mur de base:*BRIQUE 37 (20 +INT 13+2 + EXT 2) (Iso+BA13)(enduit):...) | In | ExtendToStructure | LoadBearing
4329853 | Rez de chaussée (SD) | yes | yes
4482242 | Rez de chaussée (SD) | no | yes
4742524 | ***R+1 (SD)*** | yes | no
4861942 | ***R+1 (SD)*** | yes | yes
4990944 | ***R+1 (SD)*** | yes | no

# IfcWall: Mur de base:*Mur (37) maçonné isolé + enduit + terrasson zinc, Mur de base:*Mur (37) maçonné isolé + enduit + terrasson zinc:4832661
In: Rez de chaussée (SD)
Type - PredefinedType: STANDARD; Material: __ ENDUIT_Blanc 2 cm, __ BETON_parpaings 20 cm, __ ISOLANT (pat 1) 13 cm, __ ENDUIT_Blanc 2 cm
Type - Pset_ReinforcementBarPitchOfWall - Description: Enduit ton blanc
Type - Pset_WallCommon - IsExternal: yes
Pset_QuantityTakeOff - Reference: *Mur (37) maçonné isolé + enduit + terrasson zinc; sets with these values: 2
Pset_WallCommon - LoadBearing: yes; ExtendToStructure: no; Reference: *Mur (37) maçonné isolé + enduit + terrasson zinc

# IfcWall: Mur de base:*Mur (45) maçonné isolé + parement pierre, Mur de base:*Mur (45) maçonné isolé + parement pierre:4484855
In: Rez de chaussée (SD)
Type - PredefinedType: STANDARD; Material: __ PIERRE______________________TEST 10 cm, __ BETON_parpaings 20 cm, __ ISOLANT (pat 1) 13 cm, __ ENDUIT_Blanc 2 cm
Type - Pset_ReinforcementBarPitchOfWall - Description: Couronnement zinc à ourlet
Type - Pset_WallCommon - IsExternal: yes
Pset_QuantityTakeOff - Reference: *Mur (45) maçonné isolé + parement pierre; sets with these values: 2
Pset_WallCommon - LoadBearing: yes; ExtendToStructure: no; Reference: *Mur (45) maçonné isolé + parement pierre

# IfcWall: Mur de base:*Mur (45) maçonné isolé + parement pierre + couronnement zinc, Mur de base:*Mur (45) maçonné isolé + parement pierre + couronnement zinc:4695436
In: Rez de chaussée (SD)
Type - PredefinedType: STANDARD; Material: __ PIERRE______________________TEST 10 cm, __ BETON_parpaings 20 cm, __ ISOLANT (pat 1) 13 cm, __ ENDUIT_Blanc 2 cm
Type - Pset_ReinforcementBarPitchOfWall - Description: Couverture à coulisseau
Type - Pset_WallCommon - IsExternal: yes
Pset_QuantityTakeOff - Reference: *Mur (45) maçonné isolé + parement pierre + couronnement zinc; sets with these values: 2
Pset_WallCommon - ExtendToStructure: no; LoadBearing: no; Reference: *Mur (45) maçonné isolé + parement pierre + couronnement zinc

# IfcWallStandardCase: Mur de base:*BETON 20, Mur de base:*BETON 20:4812454
In: _Rez de chaussée Séjour
Type - PredefinedType: STANDARD; Material: Béton, précoulé 20 cm
Type - Pset_ReinforcementBarPitchOfWall - Description: M1a
Type - Pset_WallCommon - IsExternal: yes; ThermalTransmittance: 5.23 kg/K/s3
Pset_QuantityTakeOff - Reference: *BETON 20; sets with these values: 2
Pset_WallCommon - LoadBearing: yes; ExtendToStructure: no; Reference: *BETON 20

# IfcWallStandardCase: Mur de base:*BETON 22 (20 + EXT 2) (enduit) + couronnement zinc (4)
In: ***R+1 (SD)***
Type - PredefinedType: STANDARD; Material: __ ENDUIT_Blanc 2 cm, __ ENDUIT_Blanc 20 cm
Type - Pset_ReinforcementBarPitchOfWall - Description: Couverture à coulisseau
Type - Pset_WallCommon - IsExternal: yes
Pset_QuantityTakeOff - Reference: *BETON 22 (20 + EXT 2) (enduit) + couronnement zinc; sets with these values: 2
Pset_WallCommon - ExtendToStructure: no; LoadBearing: no; Reference: *BETON 22 (20 + EXT 2) (enduit) + couronnement zinc
Name (Mur de base:*BETON 22 (20 + EXT 2) (enduit) + couronnement zinc:...)
4794457
4837642
4840499
5118379

# IfcWallStandardCase: Mur de base:*BETON 22 (20 + EXT 2) (enduit) + couronnement zinc retourné, Mur de base:*BETON 22 (20 + EXT 2) (enduit) + couronnement zinc retourné:5114859
In: ***R+1 (SD)***
Type - PredefinedType: STANDARD; Material: __ ENDUIT_Blanc 2 cm, __ BOIS (charpente) 22 cm, __ ENDUIT_Blanc 2 cm
Type - Pset_ReinforcementBarPitchOfWall - Description: Couronnement zinc à ourlet
Type - Pset_WallCommon - IsExternal: yes
Pset_QuantityTakeOff - Reference: *BETON 22 (20 + EXT 2) (enduit) + couronnement zinc retourné; sets with these values: 2
Pset_WallCommon - ExtendToStructure: no; LoadBearing: no; Reference: *BETON 22 (20 + EXT 2) (enduit) + couronnement zinc retourné

# IfcWallStandardCase: Mur de base:*BETON 22 (20 + EXT 2) (parement) (2)
In: Rez de chaussée (SD)
Type - PredefinedType: STANDARD; Material: __ PIERRE______________________TEST 2 cm, __ BETON______________________TEST 20 cm
Type - Pset_ReinforcementBarPitchOfWall - Description: M1c
Type - Pset_WallCommon - IsExternal: yes
Pset_QuantityTakeOff - Reference: *BETON 22 (20 + EXT 2) (parement); sets with these values: 2
Pset_WallCommon - ExtendToStructure: no; LoadBearing: no; Reference: *BETON 22 (20 + EXT 2) (parement)
Name (Mur de base:*BETON 22 (20 + EXT 2) (parement):...)
4804734
4805723

# IfcWallStandardCase: Mur de base:*BETON 22 (20 + EXT 2) (parement) + couronnement zinc (6)
In: ***R+1 (SD)***
Type - PredefinedType: STANDARD; Material: __ PIERRE______________________TEST 10 cm, Béton, précoulé 20 cm
Type - Pset_ReinforcementBarPitchOfWall - Description: Couverture à coulisseau
Type - Pset_WallCommon - IsExternal: yes; ThermalTransmittance: 5.23 kg/K/s3
Pset_QuantityTakeOff - Reference: *BETON 22 (20 + EXT 2) (parement) + couronnement zinc; sets with these values: 2
Pset_WallCommon - ExtendToStructure: no; LoadBearing: no; Reference: *BETON 22 (20 + EXT 2) (parement) + couronnement zinc
Name (Mur de base:*BETON 22 (20 + EXT 2) (parement) + couronnement zinc:...)
4789850
4794325
4794384
4796458
4796506
4838050

# IfcWallStandardCase: Mur de base:*BRIQUE 10 + Enduit (5)
Type - PredefinedType: STANDARD; Material: __ ENDUIT_Blanc 1 cm, __ BRIQUE______________________TEST 10 cm
Type - Pset_ReinforcementBarPitchOfWall - Description: M2g
Type - Pset_WallCommon - IsExternal: yes
Pset_QuantityTakeOff - Reference: *BRIQUE 10 + Enduit; sets with these values: 2
Pset_WallCommon - ExtendToStructure: no; Reference: *BRIQUE 10 + Enduit
Name (Mur de base:*BRIQUE 10 + Enduit:...) | In | LoadBearing | Group
4482397 | _Rez de chaussée Séjour | yes
4986703 | ***R+1 (SD)*** | no | Groupe de modèles:Cheminée:4986707
4986704 | ***R+1 (SD)*** | no | Groupe de modèles:Cheminée:4986707
4986705 | ***R+1 (SD)*** | no | Groupe de modèles:Cheminée:4986707
4986706 | ***R+1 (SD)*** | no | Groupe de modèles:Cheminée:4986707

# IfcWallStandardCase: Mur de base:*BRIQUE 24 (20 + INT 2 + EXT 2) (enduit 2 faces) (10)
Type - PredefinedType: STANDARD; Material: __ ENDUIT_Blanc 2 cm, Béton, précoulé 20 cm, __ ENDUIT_Blanc 2 cm
Type - Pset_ReinforcementBarPitchOfWall - Description: M2c
Type - Pset_WallCommon - IsExternal: yes; ThermalTransmittance: 5.23 kg/K/s3
Pset_QuantityTakeOff - Reference: *BRIQUE 24 (20 + INT 2 + EXT 2) (enduit 2 faces); sets with these values: 2
Pset_WallCommon - Reference: *BRIQUE 24 (20 + INT 2 + EXT 2) (enduit 2 faces)
Name (Mur de base:*BRIQUE 24 (20 + INT 2 + EXT 2) (enduit 2 faces):...) | In | LoadBearing | ExtendToStructure
4329864 | Rez de chaussée | yes | no
4329883 | Rez de chaussée | yes | no
4495790 | Rez de chaussée | yes | no
4639534 | _Rez de chaussée Séjour | yes | yes
4686350 | _R+1 | yes | yes
4687385 | _R+1 | yes | yes
4687428 | _R+1 | no | yes
4687855 | _R+1 | no | yes
4982750 | Rez de chaussée | yes | no
5084260 | Rez de chaussée | yes | no

# IfcWallStandardCase: Mur de base:*BRIQUE 37 (20 +INT 13+2 + EXT 2) (Iso+BA13)(enduit) (22)
Type - PredefinedType: STANDARD; Material: __ ENDUIT_Blanc 2 cm, __ BETON_parpaings 20 cm, __ ISOLANT (pat 1) 13 cm, __ ENDUIT_Blanc 2 cm
Type - Pset_ReinforcementBarPitchOfWall - Description: Enduit ton blanc
Type - Pset_WallCommon - IsExternal: yes
Pset_QuantityTakeOff - Reference: *BRIQUE 37 (20 +INT 13+2 + EXT 2) (Iso+BA13)(enduit); sets with these values: 2
Pset_WallCommon - Reference: *BRIQUE 37 (20 +INT 13+2 + EXT 2) (Iso+BA13)(enduit)
Name (Mur de base:*BRIQUE 37 (20 +INT 13+2 + EXT 2) (Iso+BA13)(enduit):...) | In | ExtendToStructure | LoadBearing
4329848 | Rez de chaussée (SD) | yes | yes
4329851 | Rez de chaussée (SD) | yes | yes
4329857 | Rez de chaussée | no | yes
4329863 | Rez de chaussée (SD) | yes | yes
4329865 | Rez de chaussée (SD) | no | yes
4329866 | Rez de chaussée (SD) | no | yes
4329877 | Rez de chaussée (SD) | no | yes
4329902 | _R+1 | no | yes
4329903 | _R+1 | yes | yes
4329906 | _R+1 | yes | yes
4477212 | Rez de chaussée (SD) | no | yes
4683826 | _R+1 | yes | yes
4684914 | _R+1 | no | yes
4834914 | _Rez de chaussée Séjour | no | yes
4838553 | _Rez de chaussée Séjour | no | yes
4838980 | _Rez de chaussée Séjour | no | yes
4850615 | Rez de chaussée (SD) | no | yes
4952141 | _R+1 | yes | yes
4953125 | _R+1 | yes | yes
5020648 | Rez de chaussée (SD) | no | yes
5030254 | _R+1 | no | no
5116570 | Rez de chaussée (SD) | no | yes

# IfcWallStandardCase: Mur de base:*BRIQUE 37 (20 +INT 13+2 + EXT 2) (Iso+BA13)(parement) (4)
Type - PredefinedType: STANDARD; Material: __ PIERRE______________________TEST 2 cm, __ BETON_parpaings 20 cm, __ ISOLANT (pat 1) 13 cm, __ ENDUIT_Blanc 2 cm
Type - Pset_ReinforcementBarPitchOfWall - Description: Mur en parement pierre
Type - Pset_WallCommon - IsExternal: yes
Pset_QuantityTakeOff - Reference: *BRIQUE 37 (20 +INT 13+2 + EXT 2) (Iso+BA13)(parement); sets with these values: 2
Pset_WallCommon - LoadBearing: yes; Reference: *BRIQUE 37 (20 +INT 13+2 + EXT 2) (Iso+BA13)(parement)
Name (Mur de base:*BRIQUE 37 (20 +INT 13+2 + EXT 2) (Iso+BA13)(parement):...) | In | ExtendToStructure
4482134 | Rez de chaussée (SD) | no
4784465 | Rez de chaussée | yes
4785176 | Rez de chaussée | yes
4834657 | _Rez de chaussée Séjour | no

# IfcWallStandardCase: Mur de base:*BRIQUE 37 (20 +INT 6+2 + EXT 2) (Iso+BA13)(enduit), Mur de base:*BRIQUE 37 (20 +INT 6+2 + EXT 2) (Iso+BA13)(enduit):5071584
In: Rez de chaussée (SD)
Type - PredefinedType: STANDARD; Material: __ ENDUIT_Blanc 2 cm, __ BETON_parpaings 20 cm, __ ISOLANT (pat 1) 5 cm, __ ENDUIT_Blanc 2 cm
Type - Pset_ReinforcementBarPitchOfWall - Description: Enduit ton blanc
Type - Pset_WallCommon - IsExternal: yes
Pset_QuantityTakeOff - Reference: *BRIQUE 37 (20 +INT 6+2 + EXT 2) (Iso+BA13)(enduit); sets with these values: 2
Pset_WallCommon - LoadBearing: yes; ExtendToStructure: no; Reference: *BRIQUE 37 (20 +INT 6+2 + EXT 2) (Iso+BA13)(enduit)

# IfcWallStandardCase: Mur de base:*Bois + Iso+BA13 (e27), Mur de base:*Bois + Iso+BA13 (e27):5029755
In: _R+1
Type - PredefinedType: STANDARD; Material: __ ENDUIT_Blanc 2 cm, __ ISOLANT (pat 1) 13 cm, __ BOIS (charpente) 10 cm, __ ENDUIT_Blanc 2 cm
Type - Pset_WallCommon - IsExternal: yes
Pset_QuantityTakeOff - Reference: *Bois + Iso+BA13 (e27); sets with these values: 2
Pset_WallCommon - ExtendToStructure: yes; LoadBearing: no; Reference: *Bois + Iso+BA13 (e27)

# IfcWallStandardCase: Mur de base:*Cloison 72/48 cm (16)
Type - PredefinedType: STANDARD; Material: __ BA 13 7 cm
Type - Pset_ReinforcementBarPitchOfWall - Description: C2
Type - Pset_WallCommon - IsExternal: yes
Pset_QuantityTakeOff - Reference: *Cloison 72/48 cm; sets with these values: 2
Pset_WallCommon - Reference: *Cloison 72/48 cm; LoadBearing: no
Name (Mur de base:*Cloison 72/48 cm:...) | In | ExtendToStructure
4478370 | Rez de chaussée | no
4479988 | Rez de chaussée | no
4480123 | Rez de chaussée | no
4685723 | _R+1 | no
4686112 | _R+1 | no
4686150 | _R+1 | no
4688203 | _R+1 | no
4827527 | Rez de chaussée | no
4827528 | Rez de chaussée | no
4872756 | _Rez de chaussée Séjour | yes
4919170 | Rez de chaussée | no
4919204 | Rez de chaussée | no
4974939 | Rez de chaussée | no
4975029 | Rez de chaussée | no
5102746 | Rez de chaussée | no
5122360 | Rez de chaussée | no

# IfcWallStandardCase: Mur de base:*Mur (45) maçonné isolé + parement pierre (6)
Type - PredefinedType: STANDARD; Material: __ PIERRE______________________TEST 10 cm, __ BETON_parpaings 20 cm, __ ISOLANT (pat 1) 13 cm, __ ENDUIT_Blanc 2 cm
Type - Pset_ReinforcementBarPitchOfWall - Description: Couronnement zinc à ourlet
Type - Pset_WallCommon - IsExternal: yes
Pset_QuantityTakeOff - Reference: *Mur (45) maçonné isolé + parement pierre; sets with these values: 2
Pset_WallCommon - LoadBearing: yes; ExtendToStructure: no; Reference: *Mur (45) maçonné isolé + parement pierre
Name (Mur de base:*Mur (45) maçonné isolé + parement pierre:...) | In
4483016 | _Rez de chaussée Séjour
4484906 | Rez de chaussée (SD)
4756898 | Rez de chaussée (SD)
4832463 | Rez de chaussée (SD)
4834276 | Rez de chaussée (SD)
4969493 | Rez de chaussée (SD)

# IfcWallStandardCase: Mur de base:*Mur (45) maçonné isolé + parement pierre + couronnement zinc, Mur de base:*Mur (45) maçonné isolé + parement pierre + couronnement zinc:4482014
In: _Rez de chaussée Séjour
Type - PredefinedType: STANDARD; Material: __ PIERRE______________________TEST 10 cm, __ BETON_parpaings 20 cm, __ ISOLANT (pat 1) 13 cm, __ ENDUIT_Blanc 2 cm
Type - Pset_ReinforcementBarPitchOfWall - Description: Couverture à coulisseau
Type - Pset_WallCommon - IsExternal: yes
Pset_QuantityTakeOff - Reference: *Mur (45) maçonné isolé + parement pierre + couronnement zinc; sets with these values: 2
Pset_WallCommon - ExtendToStructure: no; LoadBearing: no; Reference: *Mur (45) maçonné isolé + parement pierre + couronnement zinc

# IfcWallStandardCase: Mur de base:*Mur (8) Parement pierre, Mur de base:*Mur (8) Parement pierre:5080823
In: Rez de chaussée (SD)
Type - PredefinedType: STANDARD; Material: __ PIERRE______________________TEST 8 cm
Type - Pset_ReinforcementBarPitchOfWall - Description: Parement pierre
Type - Pset_WallCommon - IsExternal: yes
Pset_QuantityTakeOff - Reference: *Mur (8) Parement pierre; sets with these values: 2
Pset_WallCommon - ExtendToStructure: yes; LoadBearing: yes; Reference: *Mur (8) Parement pierre

# IfcWindow: *PVC 1 VANTAIL1:OB 110x120 +VR, *PVC 1 VANTAIL1:OB 110x120 +VR:4887650
In: Rez de chaussée
Type - ParameterTakesPrecedence: no; Sizeable: no; Material: <Unnamed>, Fenêtre - Vitrage, __ PVC_blanc (menuiseries)
Type - Pset_WindowCommon - IsExternal: no
OverallHeight: 147.08 cm; OverallWidth: 115 cm
Pset_QuantityTakeOff - Reference: OB 110x120 +VR
Pset_WindowCommon - IsExternal: yes; Reference: OB 110x120 +VR

# IfcWindow: *PVC 1 VANTAIL1:OF 105x120, *PVC 1 VANTAIL1:OF 105x120:4329897
In: Rez de chaussée
Type - ParameterTakesPrecedence: no; Sizeable: no; Material: <Unnamed>, Fenêtre - Vitrage, __ PVC_blanc (menuiseries)
Type - Pset_WindowCommon - IsExternal: no
OverallHeight: 147.08 cm; OverallWidth: 110 cm
Pset_QuantityTakeOff - Reference: OF 105x120
Pset_WindowCommon - IsExternal: yes; Reference: OF 105x120

# IfcWindow: *PVC 1 VANTAIL:PF 80*220+VR (2)
Type - ParameterTakesPrecedence: no; Sizeable: no; Material: <Unnamed>, Fenêtre - Vitrage, __ METAL_gris foncé (menuiseries acier)______________________TEST
Type - Pset_WindowCommon - IsExternal: no
OverallHeight: 225.542 cm; OverallWidth: 85 cm
Pset_QuantityTakeOff - Reference: PF 80*220+VR
Pset_WindowCommon - Reference: PF 80*220+VR
Name (*PVC 1 VANTAIL:PF 80*220+VR:...) | In
4934322 | Rez de chaussée | Pset_WindowCommon - IsExternal: yes
4970051 | _Rez de chaussée Séjour

# IfcWindow: *PVC 1 VANTAIL:PF 90*220 (2)
In: Rez de chaussée
Type - ParameterTakesPrecedence: no; Sizeable: no; Material: <Unnamed>, Fenêtre - Vitrage, Fenêtre - Cadre
Type - Pset_WindowCommon - IsExternal: no
OverallHeight: 225.542 cm; OverallWidth: 95 cm
Pset_QuantityTakeOff - Reference: PF 90*220
Pset_WindowCommon - Reference: PF 90*220
Name (*PVC 1 VANTAIL:PF 90*220:...)
4329898 | Pset_WindowCommon - IsExternal: yes
5020115

# IfcWindow: 2 Vantaux - Droits:120x120 (4)
Type - OperationType: DOUBLE_PANEL_VERTICAL; ParameterTakesPrecedence: no; Sizeable: no; Material: Fenêtre - Poignée, Fenêtre - Appui, Fenêtre - Cadre, Fenêtre - Vitrage
Type - Pset_WindowCommon - IsExternal: no
OverallHeight: 205 cm; OverallWidth: 130 cm
Pset_QuantityTakeOff - Reference: 120x120
Pset_WindowCommon - Reference: 120x120
Name (2 Vantaux - Droits:120x120:...) | In
4329885 | Rez de chaussée | Pset_WindowCommon - IsExternal: yes
4329900 | Rez de chaussée
4329909 | _R+1
4813307 | _R+1

# IfcWindow: 2 Vantaux coulissants - Droits:c 200x120 +VR, 2 Vantaux coulissants - Droits:c 200x120 +VR:4834277
In: _Rez de chaussée Séjour
Type - OperationType: DOUBLE_PANEL_VERTICAL; ParameterTakesPrecedence: no; Sizeable: no; Material: Fenêtre - Poignée, Fenêtre - Appui, Fenêtre - Vitrage, __ METAL_gris foncé (menuiseries acier)______________________TEST, Fenêtre - Cadre
Type - Pset_WindowCommon - IsExternal: no; ThermalTransmittance: 3.6886 kg/K/s3
OverallHeight: 133 cm; OverallWidth: 210 cm
Pset_QuantityTakeOff - Reference: c 200x120 +VR
Pset_WindowCommon - IsExternal: yes; Reference: c 200x120 +VR

# IfcWindow: 2 Vantaux coulissants - Droits:c 220x220 +VR, 2 Vantaux coulissants - Droits:c 220x220 +VR:4917851
In: Rez de chaussée
Type - OperationType: DOUBLE_PANEL_VERTICAL; ParameterTakesPrecedence: no; Sizeable: no; Material: Fenêtre - Poignée, Fenêtre - Appui, Fenêtre - Vitrage, __ METAL_gris foncé (menuiseries acier)______________________TEST, Fenêtre - Cadre
Type - Pset_WindowCommon - IsExternal: no; ThermalTransmittance: 3.6886 kg/K/s3
OverallHeight: 233 cm; OverallWidth: 230 cm
Pset_QuantityTakeOff - Reference: c 220x220 +VR
Pset_WindowCommon - IsExternal: yes; Reference: c 220x220 +VR

# IfcWindow: 2 Vantaux coulissants - Droits:c 300x220, 2 Vantaux coulissants - Droits:c 300x220:4931038
In: _Rez de chaussée Séjour
Type - OperationType: DOUBLE_PANEL_VERTICAL; ParameterTakesPrecedence: no; Sizeable: no; Material: Fenêtre - Poignée, Fenêtre - Appui, Fenêtre - Vitrage, __ METAL_gris foncé (menuiseries acier)______________________TEST, Fenêtre - Cadre
Type - Pset_WindowCommon - IsExternal: no; ThermalTransmittance: 3.6886 kg/K/s3
OverallHeight: 233 cm; OverallWidth: 310 cm
Pset_QuantityTakeOff - Reference: c 300x220
Pset_WindowCommon - IsExternal: yes; Reference: c 300x220

# IfcWindow: Fenetre chien assis:Fenetre chien assis, Fenetre chien assis:Fenetre chien assis:4496622
In: Rez de chaussée (SD)
Type - ParameterTakesPrecedence: no; Sizeable: no; Material: __ METAL_gris foncé (menuiseries acier)______________________TEST, Fenêtre - Vitrage
Type - Pset_WindowCommon - IsExternal: no
OverallHeight: 103.618 cm; OverallWidth: 173.892 cm
Pset_QuantityTakeOff - Reference: Fenetre chien assis
Pset_WindowCommon - Reference: Fenetre chien assis

# IfcWindow: MR 1 Vantail Droit:MR 1 Vantail Droit, MR 1 Vantail Droit:MR 1 Vantail Droit:4839397
In: _Rez de chaussée Séjour
Type - ParameterTakesPrecedence: no; Sizeable: no; Material: PVC - Blanc, Fenêtre - Vitrage, __ METAL_gris foncé (menuiseries acier)______________________TEST
Type - Pset_WindowCommon - IsExternal: no
OverallHeight: 152.5 cm; OverallWidth: 47.5 cm
Pset_QuantityTakeOff - Reference: MR 1 Vantail Droit
Pset_WindowCommon - IsExternal: yes; Reference: MR 1 Vantail Droit

# IfcWindow: OPTIMAL Top Turn Single Window-1:200x120 +VR (2)
In: Rez de chaussée
Type - ParameterTakesPrecedence: no; Sizeable: no; Material: Fenêtre - Vitrage, __ METAL_gris foncé (menuiseries acier)______________________TEST
Type - Pset_ManufacturerTypeInformation - Manufacturer: Svenska Fönster
Type - Pset_WindowCommon - IsExternal: no
OverallHeight: 122 cm; OverallWidth: 200 cm
Pset_QuantityTakeOff - Reference: 200x120 +VR
Pset_WindowCommon - Reference: 200x120 +VR
Name (OPTIMAL Top Turn Single Window-1:200x120 +VR:...)
4832554 | Pset_WindowCommon - IsExternal: yes
4833477

# IfcWindow: OPTIMAL Top Turn Single Window-1:200x120 PVC (2)
Type - ParameterTakesPrecedence: no; Sizeable: no; Material: Fenêtre - Vitrage, PVC - Blanc
Type - Pset_ManufacturerTypeInformation - Manufacturer: Svenska Fönster
Type - Pset_WindowCommon - IsExternal: no
OverallHeight: 122 cm; OverallWidth: 200 cm
Pset_QuantityTakeOff - Reference: 200x120 PVC
Pset_WindowCommon - Reference: 200x120 PVC
Name (OPTIMAL Top Turn Single Window-1:200x120 PVC:...) | In
4329899 | _Rez de chaussée Séjour | Pset_WindowCommon - IsExternal: yes
4329908 | _R+1

# IfcWindow: OPTIMAL Top Turn Single Window-1:OPTIMAL Top Turn Single Window 50x100, OPTIMAL Top Turn Single Window-1:OPTIMAL Top Turn Single Window 50x100:4329901
In: Rez de chaussée
Type - ParameterTakesPrecedence: no; Sizeable: no; Material: Glass, White NCS S0502-Y
Type - Pset_ManufacturerTypeInformation - Manufacturer: Svenska Fönster
Type - Pset_WindowCommon - IsExternal: no
OverallHeight: 100 cm; OverallWidth: 50 cm
Pset_QuantityTakeOff - Reference: OPTIMAL Top Turn Single Window 50x100
Pset_WindowCommon - IsExternal: yes; Reference: OPTIMAL Top Turn Single Window 50x100

# IfcWindow: OPTIMAL Top Turn Single Window-1:c 300x170 +VR, OPTIMAL Top Turn Single Window-1:c 300x170 +VR:4487097
In: _Rez de chaussée Séjour
Type - ParameterTakesPrecedence: no; Sizeable: no; Material: Fenêtre - Vitrage, __ METAL_gris foncé (menuiseries acier)______________________TEST
Type - Pset_ManufacturerTypeInformation - Manufacturer: Svenska Fönster
Type - Pset_WindowCommon - IsExternal: no
OverallHeight: 172 cm; OverallWidth: 300 cm
Pset_QuantityTakeOff - Reference: c 300x170 +VR
Pset_WindowCommon - IsExternal: yes; Reference: c 300x170 +VR

# IfcWindow: OPTIMAL Top Turn Single Window-1:fixe 110x220, OPTIMAL Top Turn Single Window-1:fixe 110x220:4931289
In: _Rez de chaussée Séjour
Type - ParameterTakesPrecedence: no; Sizeable: no; Material: Glass, __ METAL_gris foncé (menuiseries acier)______________________TEST
Type - Pset_ManufacturerTypeInformation - Manufacturer: Svenska Fönster
Type - Pset_WindowCommon - IsExternal: no
OverallHeight: 220 cm; OverallWidth: 110 cm
Pset_QuantityTakeOff - Reference: fixe 110x220
Pset_WindowCommon - IsExternal: yes; Reference: fixe 110x220
